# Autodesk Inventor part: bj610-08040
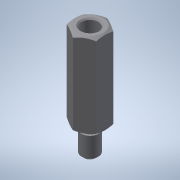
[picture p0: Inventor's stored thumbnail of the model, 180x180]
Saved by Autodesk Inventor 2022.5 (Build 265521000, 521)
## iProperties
Created: 2016-12
Part Number: bj610-08040
Material: 一般
Document SubType Name: Modeling
Designer: imaocorp
Density: 1 g/cm^3
Appearance: 既定
Author: imaocorp
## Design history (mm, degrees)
node "bj610-08040.x_t1"
node "bj610-08040"
node "Base1"
